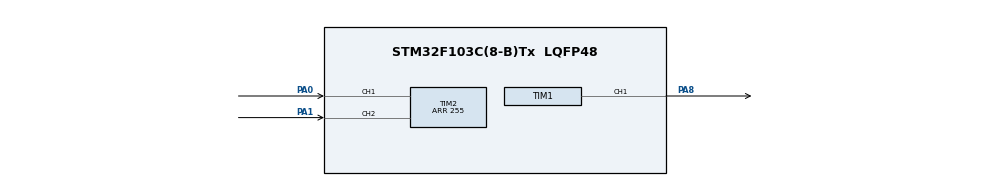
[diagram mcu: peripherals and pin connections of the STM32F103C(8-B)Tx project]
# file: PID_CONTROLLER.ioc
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Mcu.Family=STM32F1
Mcu.Name=STM32F103C(8-B)Tx
Mcu.Package=LQFP48
NVIC.PriorityGroup=NVIC_PRIORITYGROUP_4
PA0-WKUP.Signal=S_TIM2_CH1_ETR
PA1.Signal=S_TIM2_CH2
PA13.Mode=Serial_Wire
PA13.Signal=SYS_JTMS-SWDIO
PA14.Mode=Serial_Wire
PA14.Signal=SYS_JTCK-SWCLK
PA8.Signal=S_TIM1_CH1
PD0-OSC_IN.Mode=HSE-External-Oscillator
PD0-OSC_IN.Signal=RCC_OSC_IN
PD1-OSC_OUT.Mode=HSE-External-Oscillator
PD1-OSC_OUT.Signal=RCC_OSC_OUT
ProjectManager.HeapSize=0x200
ProjectManager.StackSize=0x400
ProjectManager.TargetToolchain=STM32CubeIDE
RCC.AHBFreq_Value=72000000
RCC.APB1CLKDivider=RCC_HCLK_DIV2
RCC.APB1Freq_Value=36000000
RCC.APB1TimFreq_Value=72000000
RCC.APB2Freq_Value=72000000
RCC.APB2TimFreq_Value=72000000
RCC.HCLKFreq_Value=72000000
RCC.PLLMUL=RCC_PLL_MUL9
RCC.PLLSourceVirtual=RCC_PLLSOURCE_HSE
RCC.SYSCLKFreq_VALUE=72000000
RCC.SYSCLKSource=RCC_SYSCLKSOURCE_PLLCLK
RCC.USBFreq_Value=72000000
SH.S_TIM1_CH1.0=TIM1_CH1,PWM Generation1 CH1
SH.S_TIM2_CH1_ETR.0=TIM2_CH1,Encoder_Interface
SH.S_TIM2_CH2.0=TIM2_CH2,Encoder_Interface
TIM1.Channel-PWM\ Generation1\ CH1=TIM_CHANNEL_1
TIM2.EncoderMode=TIM_ENCODERMODE_TI12
TIM2.Period=255
board=custom

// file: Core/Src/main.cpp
/* USER CODE BEGIN Header */
/**
  ******************************************************************************
  * @file           : main.c
  * @brief          : Main program body
  ******************************************************************************
  * @attention
  *
  * Copyright (c) 2024 STMicroelectronics.
  * All rights reserved.
  *
  * This software is licensed under terms that can be found in the LICENSE file
  * in the root directory of this software component.
  * If no LICENSE file comes with this software, it is provided AS-IS.
  *
  ******************************************************************************
  */
/* USER CODE END Header */
#include "main.h"

/* USER CODE BEGIN Includes */
#include "Motor.h"
#include <math.h>
/* USER CODE END Includes */

TIM_HandleTypeDef htim1;
TIM_HandleTypeDef htim2;

/* USER CODE BEGIN PV */
float Kp = 1.0f;
float Ki = 0.0f;
float Kd = 0.0f;

float desired_angle = 180.0f;
float prev_error = 0.0f;
float integral = 0.0f;
float derivative = 0.0f;
float pid_output = 0.0f;
float output =0;
uint32_t count =0;
int16_t angle = 0;
const float cpr = 50.0f;

/* USER CODE END PV */

void SystemClock_Config(void);
static void MX_GPIO_Init(void);
static void MX_TIM2_Init(void);
static void MX_TIM1_Init(void);

//PID control function
float PID_Controller(float desired_angle, float current_angle) {

    float error = desired_angle - current_angle;
    float proportional = Kp * error;
    float delta_time = (1/100);
    /*if(delta_time == 0 ){
    	return pid_output;
    }*/
    integral += error * delta_time;
    float integral_term = Ki * integral;
    float derivative = (error - prev_error );
    float derivative_term = Kd * derivative;
    pid_output = proportional + integral_term + derivative_term;
    prev_error = error;
    //last_time = current_time;
    return pid_output;
}

int main(void)
{

  /* MCU Configuration--------------------------------------------------------*/

  /* Reset of all peripherals, Initializes the Flash interface and the Systick. */
  HAL_Init();

  /* Configure the system clock */
  SystemClock_Config();

  /* Initialize all configured peripherals */
  MX_GPIO_Init();
  MX_TIM2_Init();
  MX_TIM1_Init();

  /* USER CODE BEGIN 2 */
  /* USER CODE BEGIN 2 */
  HAL_TIM_Encoder_Start(&htim2, TIM_CHANNEL_ALL);
  MOTOR MotorA(GPIOA,GPIO_PIN_9,GPIOA, GPIO_PIN_10);
  MotorA.motor_init(&htim1, TIM_CHANNEL_1);

  /* USER CODE END 2 */

  /* Infinite loop */
  /* USER CODE BEGIN WHILE */
  while (1)
  {
	  count = (TIM2->CNT);
	  if (count >= TIM2->ARR) {
	          count = 0;  // Reset the count if it exceeds the max range
	  }
	  angle = ((float)count / cpr) * 360.0f;
	  if (angle >= 360) {
	      angle -= 360;
	  }
	  HAL_TIM_IC_CaptureCallback(&htim2);
	  HAL_Delay(1);

	  int32_t pid_output = PID_Controller(desired_angle, angle);

	  if(pid_output>255){
		  output = 255;
	  }
	  else if (pid_output< -255){
		  output = -255;
	  }else{
		  output= pid_output;
	  }

	  if(angle > desired_angle + 3){
		  MotorA.clockwise((uint16_t)pid_output);
	  }
	  else if(angle < desired_angle - 3){
		  MotorA.anti_clockwise((uint16_t)-pid_output);
	  }
	  else{
		  MotorA.brake();
		  }

  }

		  /*
		  if(count > 28 - 1){
			  MotorA.clockwise(6553);
		  }
		  if(count < 28 + 1){
			  MotorA.anti_clockwise(6553);
		  }
		  if(count == 28){
			  MotorA.jam();
*/

    /* USER CODE END WHILE */

}

void SystemClock_Config(void)
{
  RCC_OscInitTypeDef RCC_OscInitStruct = {0};
  RCC_ClkInitTypeDef RCC_ClkInitStruct = {0};

  /** Initializes the RCC Oscillators according to the specified parameters
  * in the RCC_OscInitTypeDef structure.
  */
  RCC_OscInitStruct.OscillatorType = RCC_OSCILLATORTYPE_HSI;
  RCC_OscInitStruct.HSIState = RCC_HSI_ON;
  RCC_OscInitStruct.HSICalibrationValue = RCC_HSICALIBRATION_DEFAULT;
  RCC_OscInitStruct.PLL.PLLState = RCC_PLL_NONE;
  if (HAL_RCC_OscConfig(&RCC_OscInitStruct) != HAL_OK)
  {
    Error_Handler();
  }

  /** Initializes the CPU, AHB and APB buses clocks
  */
  RCC_ClkInitStruct.ClockType = RCC_CLOCKTYPE_HCLK|RCC_CLOCKTYPE_SYSCLK
                              |RCC_CLOCKTYPE_PCLK1|RCC_CLOCKTYPE_PCLK2;
  RCC_ClkInitStruct.SYSCLKSource = RCC_SYSCLKSOURCE_HSI;
  RCC_ClkInitStruct.AHBCLKDivider = RCC_SYSCLK_DIV1;
  RCC_ClkInitStruct.APB1CLKDivider = RCC_HCLK_DIV1;
  RCC_ClkInitStruct.APB2CLKDivider = RCC_HCLK_DIV1;

  if (HAL_RCC_ClockConfig(&RCC_ClkInitStruct, FLASH_LATENCY_0) != HAL_OK)
  {
    Error_Handler();
  }
}

static void MX_TIM1_Init(void)
{

  TIM_ClockConfigTypeDef sClockSourceConfig = {0};
  TIM_MasterConfigTypeDef sMasterConfig = {0};
  TIM_OC_InitTypeDef sConfigOC = {0};
  TIM_BreakDeadTimeConfigTypeDef sBreakDeadTimeConfig = {0};

  htim1.Instance = TIM1;
  htim1.Init.Prescaler = 0;
  htim1.Init.CounterMode = TIM_COUNTERMODE_UP;
  htim1.Init.Period = 255;
  htim1.Init.ClockDivision = TIM_CLOCKDIVISION_DIV1;
  htim1.Init.RepetitionCounter = 0;
  htim1.Init.AutoReloadPreload = TIM_AUTORELOAD_PRELOAD_ENABLE;
  if (HAL_TIM_Base_Init(&htim1) != HAL_OK)
  {
    Error_Handler();
  }
  sClockSourceConfig.ClockSource = TIM_CLOCKSOURCE_INTERNAL;
  if (HAL_TIM_ConfigClockSource(&htim1, &sClockSourceConfig) != HAL_OK)
  {
    Error_Handler();
  }
  if (HAL_TIM_PWM_Init(&htim1) != HAL_OK)
  {
    Error_Handler();
  }
  sMasterConfig.MasterOutputTrigger = TIM_TRGO_RESET;
  sMasterConfig.MasterSlaveMode = TIM_MASTERSLAVEMODE_DISABLE;
  if (HAL_TIMEx_MasterConfigSynchronization(&htim1, &sMasterConfig) != HAL_OK)
  {
    Error_Handler();
  }
  sConfigOC.OCMode = TIM_OCMODE_PWM1;
  sConfigOC.Pulse = 1;
  sConfigOC.OCPolarity = TIM_OCPOLARITY_HIGH;
  sConfigOC.OCNPolarity = TIM_OCNPOLARITY_HIGH;
  sConfigOC.OCFastMode = TIM_OCFAST_DISABLE;
  sConfigOC.OCIdleState = TIM_OCIDLESTATE_RESET;
  sConfigOC.OCNIdleState = TIM_OCNIDLESTATE_RESET;
  if (HAL_TIM_PWM_ConfigChannel(&htim1, &sConfigOC, TIM_CHANNEL_1) != HAL_OK)
  {
    Error_Handler();
  }
  sBreakDeadTimeConfig.OffStateRunMode = TIM_OSSR_DISABLE;
  sBreakDeadTimeConfig.OffStateIDLEMode = TIM_OSSI_DISABLE;
  sBreakDeadTimeConfig.LockLevel = TIM_LOCKLEVEL_OFF;
  sBreakDeadTimeConfig.DeadTime = 0;
  sBreakDeadTimeConfig.BreakState = TIM_BREAK_DISABLE;
  sBreakDeadTimeConfig.BreakPolarity = TIM_BREAKPOLARITY_HIGH;
  sBreakDeadTimeConfig.AutomaticOutput = TIM_AUTOMATICOUTPUT_DISABLE;
  if (HAL_TIMEx_ConfigBreakDeadTime(&htim1, &sBreakDeadTimeConfig) != HAL_OK)
  {
    Error_Handler();
  }
  HAL_TIM_MspPostInit(&htim1);

}

static void MX_TIM2_Init(void)
{

  TIM_Encoder_InitTypeDef sConfig = {0};
  TIM_MasterConfigTypeDef sMasterConfig = {0};

  htim2.Instance = TIM2;
  htim2.Init.Prescaler = 0;
  htim2.Init.CounterMode = TIM_COUNTERMODE_UP;
  htim2.Init.Period = 255;
  htim2.Init.ClockDivision = TIM_CLOCKDIVISION_DIV1;
  htim2.Init.AutoReloadPreload = TIM_AUTORELOAD_PRELOAD_ENABLE;
  sConfig.EncoderMode = TIM_ENCODERMODE_TI12;
  sConfig.IC1Polarity = TIM_ICPOLARITY_FALLING;
  sConfig.IC1Selection = TIM_ICSELECTION_DIRECTTI;
  sConfig.IC1Prescaler = TIM_ICPSC_DIV1;
  sConfig.IC1Filter = 1;
  sConfig.IC2Polarity = TIM_ICPOLARITY_FALLING;
  sConfig.IC2Selection = TIM_ICSELECTION_DIRECTTI;
  sConfig.IC2Prescaler = TIM_ICPSC_DIV1;
  sConfig.IC2Filter = 0;
  if (HAL_TIM_Encoder_Init(&htim2, &sConfig) != HAL_OK)
  {
    Error_Handler();
  }
  sMasterConfig.MasterOutputTrigger = TIM_TRGO_RESET;
  sMasterConfig.MasterSlaveMode = TIM_MASTERSLAVEMODE_DISABLE;
  if (HAL_TIMEx_MasterConfigSynchronization(&htim2, &sMasterConfig) != HAL_OK)
  {
    Error_Handler();
  }

}

static void MX_GPIO_Init(void)
{
  GPIO_InitTypeDef GPIO_InitStruct = {0};

  /* GPIO Ports Clock Enable */
  __HAL_RCC_GPIOD_CLK_ENABLE();
  __HAL_RCC_GPIOA_CLK_ENABLE();

  /*Configure GPIO pin Output Level */
  HAL_GPIO_WritePin(GPIOA, GPIO_PIN_9|GPIO_PIN_10, GPIO_PIN_RESET);

  /*Configure GPIO pins : PA9 PA10 */
  GPIO_InitStruct.Pin = GPIO_PIN_9|GPIO_PIN_10;
  GPIO_InitStruct.Mode = GPIO_MODE_OUTPUT_PP;
  GPIO_InitStruct.Pull = GPIO_NOPULL;
  GPIO_InitStruct.Speed = GPIO_SPEED_FREQ_LOW;
  HAL_GPIO_Init(GPIOA, &GPIO_InitStruct);

}

void Error_Handler(void)
{
  __disable_irq();
  while (1)
  {
  }
}
